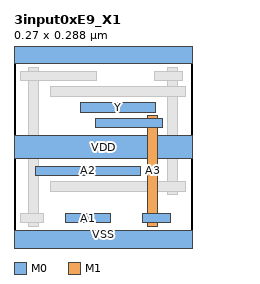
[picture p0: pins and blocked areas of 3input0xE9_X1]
MACRO 3input0xE9_X1
  CLASS CORE ;
  ORIGIN 0 0 ;
  FOREIGN 3input0xE9_X1 0 0 ;
  SIZE 0.2700 BY 0.2880 ;
  SYMMETRY X Y ;
  SITE coresite ;
  PIN A1
    DIRECTION INPUT ;
    USE SIGNAL ;
    PORT
      LAYER M0 ;
        RECT 0.0780 0.0290 0.1470 0.0430 ;
    END
  END A1
  PIN A2
    DIRECTION INPUT ;
    USE SIGNAL ;
    PORT
      LAYER M0 ;
        RECT 0.0330 0.1010 0.1920 0.1150 ;
    END
  END A2
  PIN A3
    DIRECTION INPUT ;
    USE SIGNAL ;
    PORT
      LAYER M1 ;
        RECT 0.2025 0.0240 0.2175 0.1920 ;
      LAYER M0 ;
        RECT 0.1950 0.0290 0.2370 0.0430 ;
        RECT 0.1230 0.1730 0.2250 0.1870 ;
    END
  END A3
  PIN Y
    DIRECTION OUTPUT ;
    USE SIGNAL ;
    PORT
      LAYER M0 ;
        RECT 0.1005 0.1970 0.2145 0.2110 ;
    END
  END Y
  PIN VDD
    DIRECTION INOUT ;
    USE POWER ;
    SHAPE ABUTMENT ;
    PORT
      LAYER M0 ;
        RECT 0.0000 0.1260 0.2700 0.1620 ;
    END
  END VDD
  PIN VSS
    DIRECTION INOUT ;
    USE GROUND ;
    SHAPE ABUTMENT ;
    PORT
      LAYER M0 ;
        RECT 0.0000 0.2700 0.2700 0.3060 ;
        RECT 0.0000 -0.0180 0.2700 0.0180 ;
    END
  END VSS
  OBS
    LAYER M1 ;
      RECT 0.0225 0.0240 0.0375 0.2640 ;
      RECT 0.2325 0.0720 0.2475 0.2640 ;
    LAYER V0 ;
      RECT 0.2030 0.0290 0.2170 0.0430 ;
      RECT 0.2030 0.1730 0.2170 0.1870 ;
      RECT 0.0230 0.0290 0.0370 0.0430 ;
      RECT 0.0230 0.2450 0.0370 0.2590 ;
      RECT 0.2330 0.0770 0.2470 0.0910 ;
      RECT 0.2330 0.2450 0.2470 0.2590 ;
    LAYER M0 ;
      RECT 0.0105 0.0290 0.0450 0.0430 ;
      RECT 0.0555 0.0770 0.2595 0.0910 ;
      RECT 0.0555 0.2210 0.2595 0.2350 ;
      RECT 0.0105 0.2450 0.1245 0.2590 ;
      RECT 0.2130 0.2450 0.2550 0.2590 ;
  END
END 3input0xE9_X1
